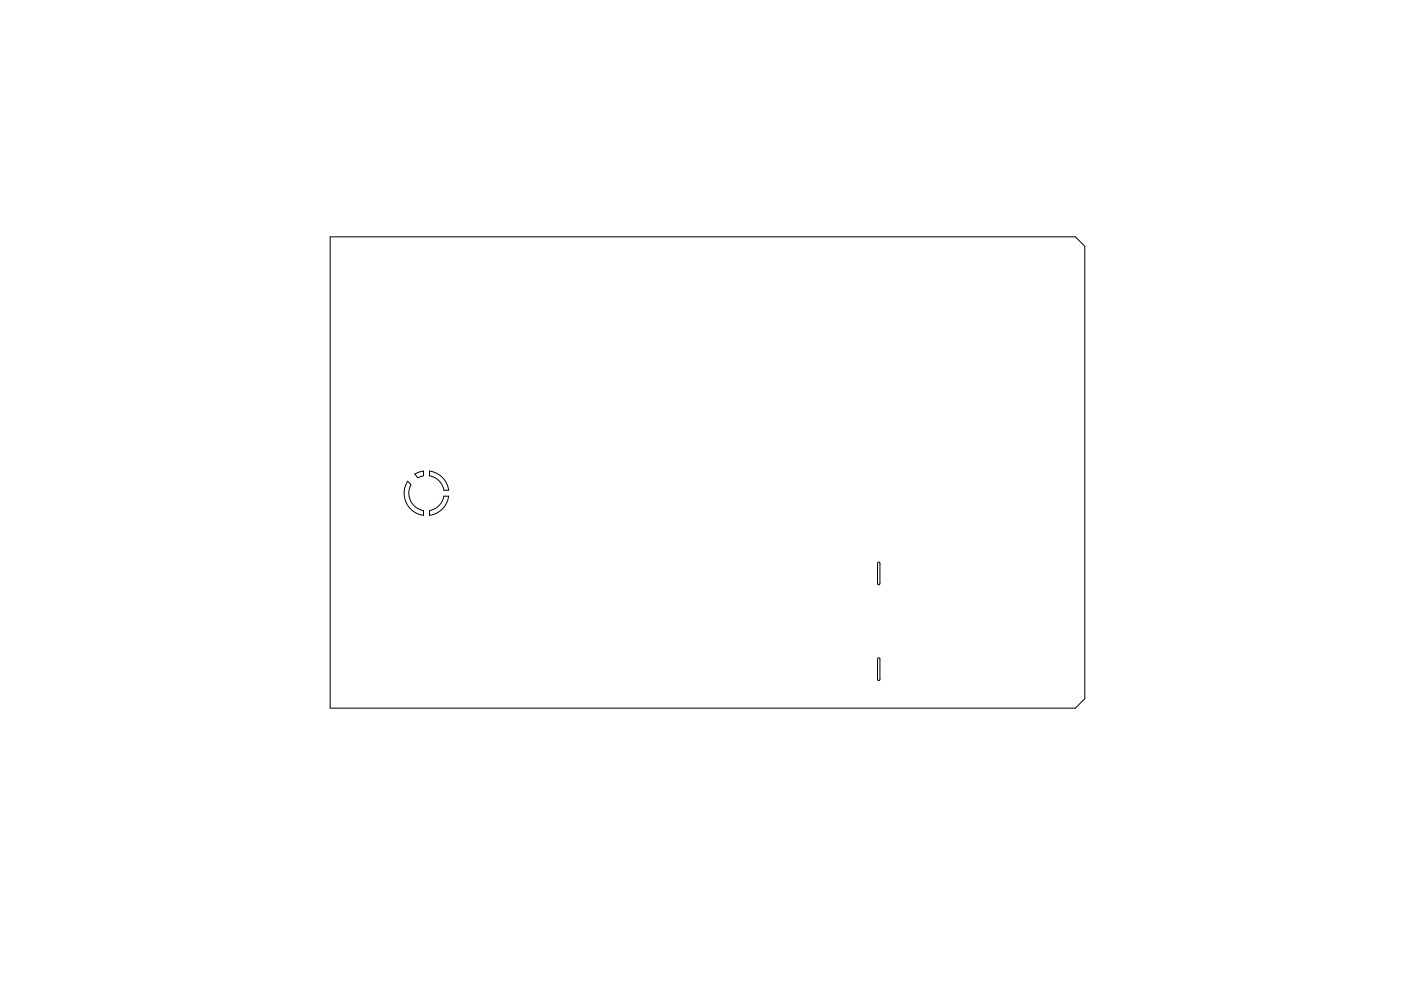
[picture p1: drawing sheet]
<svg xmlns="http://www.w3.org/2000/svg" width="297mm" height="210mm" viewBox="0 0 297 210" stroke-linecap="round" stroke-linejoin="round" font-family="sans-serif">
<path d="M70 50.2h158l2 2v96l-2 2h-158zM91.1 99.9a4.7 4.7 0 0 1 4 4.1h-1a3.7 3.7 0 0 0-3-3zM86.4 102.1l.7 .8a3.8 3.8 0 0 0 2.7 5.4v1a4.7 4.7 0 0 1-3.4-7.2zM87.9 100.6l1.9-.7v1.1l-1.2 .4zM91.1 108.3a3.7 3.7 0 0 0 3-3h1a4.7 4.7 0 0 1-4 4zM186.1 119.3h.3l.2 .2v4.3l-.3 .3-.2-.3zM186.1 139.6h.3l.2 .2v4.4l-.3 .2-.2-.3z" fill="none" stroke="#000" stroke-width=".21"/>
</svg>
